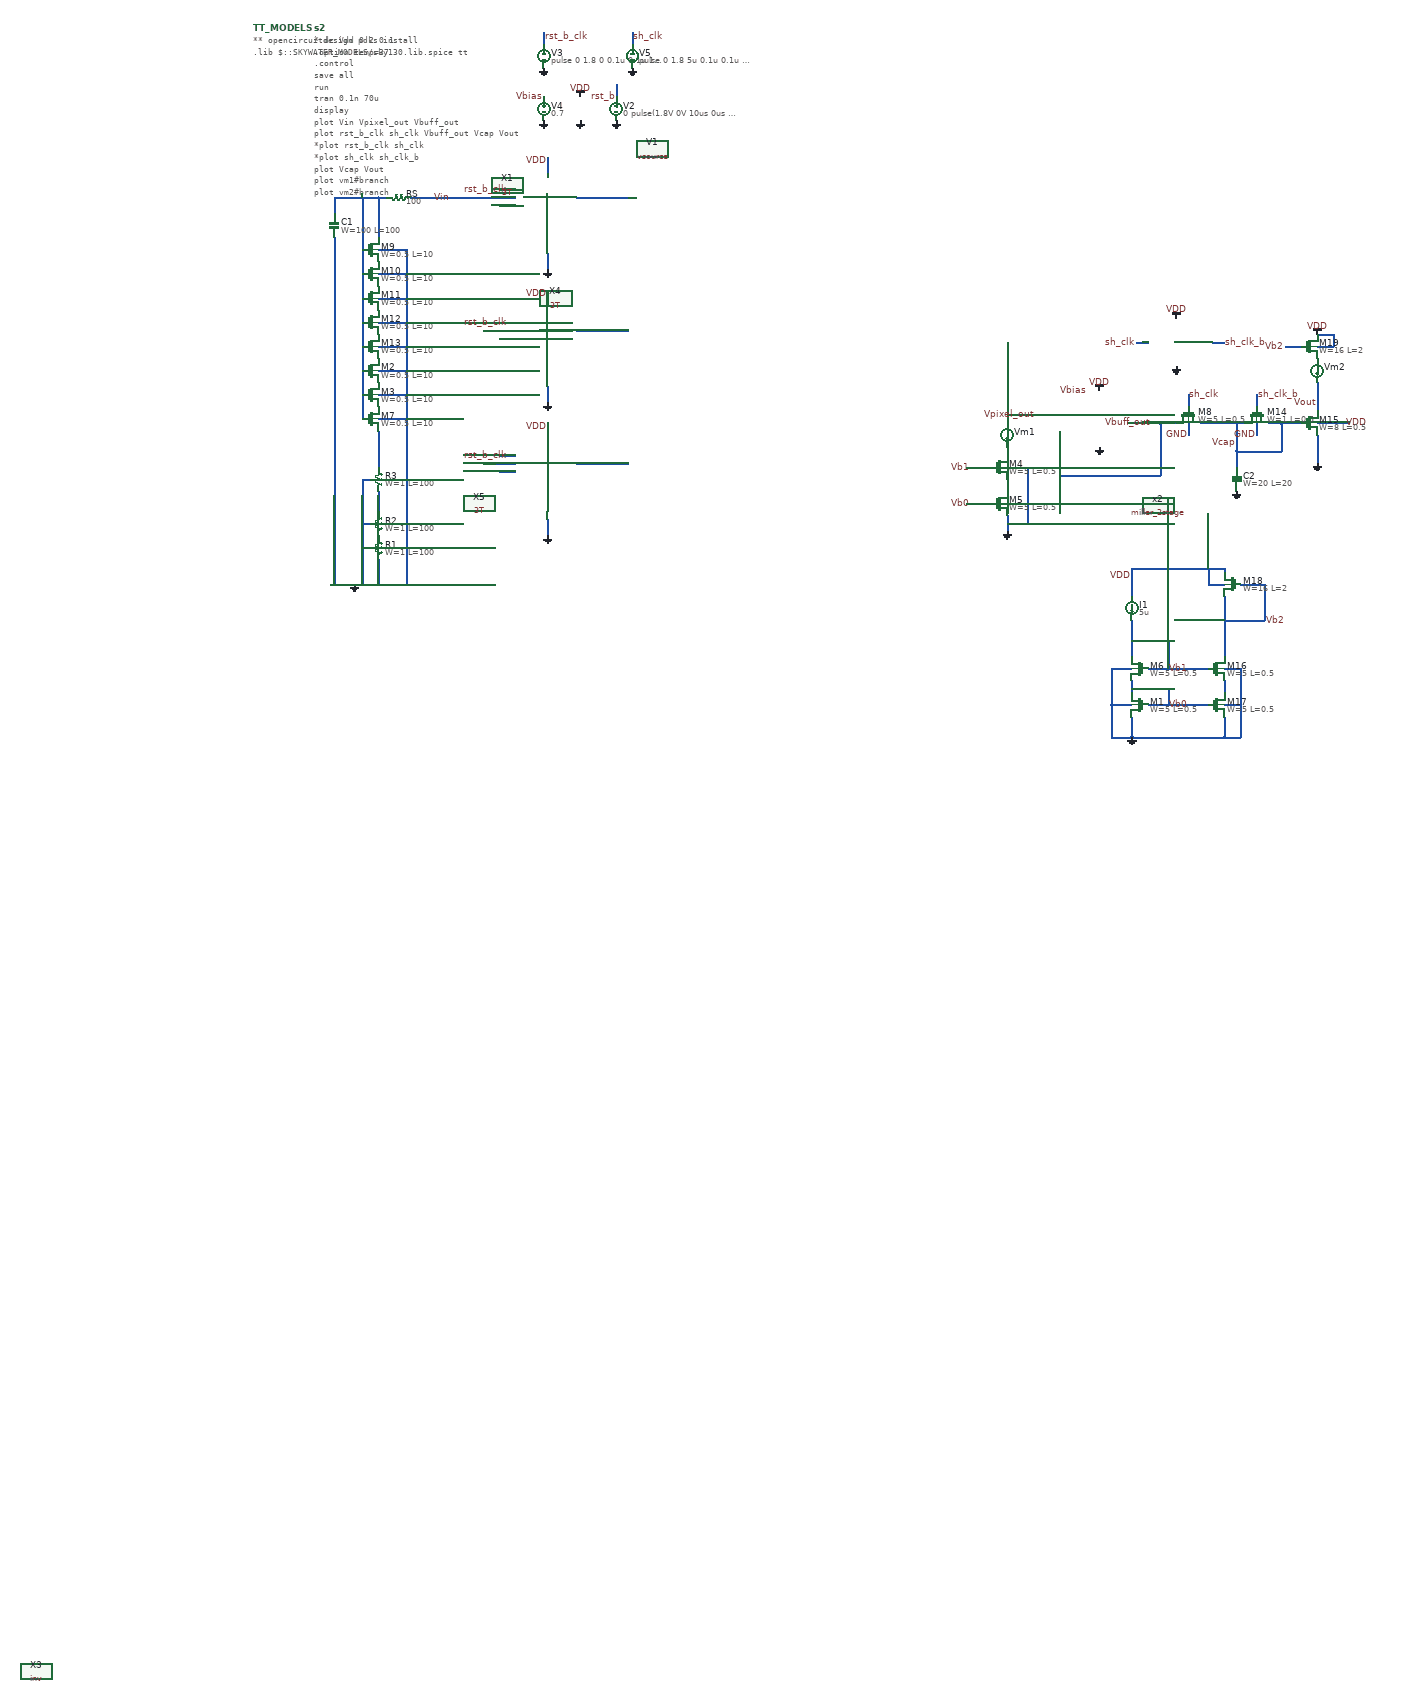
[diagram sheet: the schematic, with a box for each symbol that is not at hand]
v {xschem version=3.1.0 file_version=1.2
}
G {}
K {}
V {}
S {}
E {}
N 3910 -2230 3910 -2170 {
lab=Vpixel_out}
N 3910 -2030 3910 -2000 {
lab=#net1}
N 3910 -1940 3910 -1900 {
lab=GND}
N 3810 -1970 3870 -1970 {
lab=Vb0}
N 3810 -2060 3870 -2060 {
lab=Vb1}
N 2240 -2730 2240 -2690 {
lab=#net2}
N 2230 -1770 2340 -1770 {
lab=GND}
N 2350 -2730 2370 -2730 {
lab=#net2}
N 2430 -2730 2460 -2730 {
lab=Vin}
N 4220 -1530 4220 -1500 {
lab=Vb0}
N 4220 -1680 4220 -1590 {
lab=Vb1}
N 4220 -1440 4220 -1390 {
lab=GND}
N 4170 -1470 4220 -1470 {
lab=GND}
N 4170 -1470 4170 -1390 {
lab=GND}
N 4170 -1390 4220 -1390 {
lab=GND}
N 4170 -1560 4170 -1470 {
lab=GND}
N 4170 -1560 4220 -1560 {
lab=GND}
N 4260 -1470 4360 -1470 {
lab=Vb0}
N 4260 -1560 4360 -1560 {
lab=Vb1}
N 4220 -1630 4310 -1630 {
lab=Vb1}
N 4310 -1630 4310 -1560 {
lab=Vb1}
N 4220 -1510 4310 -1510 {
lab=Vb0}
N 4310 -1510 4310 -1470 {
lab=Vb0}
N 4220 -1810 4220 -1740 {
lab=VDD}
N 3910 -2190 4010 -2190 {
lab=Vpixel_out}
N 3910 -2110 3910 -2090 {
lab=#net3}
N 3910 -1970 3960 -1970 {
lab=GND}
N 3960 -1970 3960 -1920 {
lab=GND}
N 3910 -1920 3960 -1920 {
lab=GND}
N 3960 -2060 3960 -1970 {
lab=GND}
N 3910 -2060 3960 -2060 {
lab=GND}
N 4010 -2190 4040 -2190 {
lab=Vpixel_out}
N 2310 -2730 2310 -2660 {
lab=#net2}
N 2240 -2630 2240 -2210 {
lab=GND}
N 2240 -2210 2240 -1770 {
lab=GND}
N 2420 -2000 2420 -1770 {
lab=GND}
N 2840 -2730 2970 -2730 {
lab=#net4}
N 3910 -2370 3910 -2230 {
lab=Vpixel_out}
N 2770 -2830 2770 -2790 {
lab=VDD}
N 2770 -2590 2770 -2550 {
lab=GND}
N 2610 -2730 2690 -2730 {
lab=Vin}
N 2650 -2750 2690 -2750 {
lab=rst_b_clk}
N 2650 -2710 2690 -2710 {
lab=VDD}
N 2460 -2730 2610 -2730 {
lab=Vin}
N 2310 -1800 2310 -1770 {
lab=GND}
N 2310 -1920 2330 -1920 {
lab=GND}
N 2310 -1920 2310 -1800 {
lab=GND}
N 2350 -1970 2350 -1950 {
lab=#net5}
N 2310 -2420 2310 -2360 {
lab=#net2}
N 2310 -2480 2310 -2420 {
lab=#net2}
N 2310 -2540 2310 -2480 {
lab=#net2}
N 2310 -2600 2310 -2540 {
lab=#net2}
N 2310 -2660 2310 -2600 {
lab=#net2}
N 2350 -2600 2420 -2600 {
lab=GND}
N 2420 -2600 2420 -2210 {
lab=GND}
N 2350 -2420 2420 -2420 {
lab=GND}
N 2350 -2480 2420 -2480 {
lab=GND}
N 2350 -2540 2420 -2540 {
lab=GND}
N 2350 -2730 2350 -2630 {
lab=#net2}
N 2420 -2210 2420 -2000 {
lab=GND}
N 2350 -2360 2420 -2360 {
lab=GND}
N 2310 -2240 2310 -2180 {
lab=#net2}
N 2310 -2300 2310 -2240 {
lab=#net2}
N 2350 -2240 2420 -2240 {
lab=GND}
N 2350 -2300 2420 -2300 {
lab=GND}
N 2350 -2180 2420 -2180 {
lab=GND}
N 2310 -2360 2310 -2300 {
lab=#net2}
N 2760 -3130 2760 -3110 {
lab=rst_b_clk}
N 2760 -3140 2760 -3130 {
lab=rst_b_clk}
N 2940 -3010 2940 -2980 {
lab=rst_b}
N 2350 -2000 2350 -1970 {
lab=#net5}
N 2350 -2150 2350 -2060 {
lab=#net6}
N 2310 -2030 2330 -2030 {
lab=GND}
N 2310 -2030 2310 -1920 {
lab=GND}
N 2350 -1830 2350 -1770 {
lab=GND}
N 2310 -1860 2330 -1860 {
lab=GND}
N 4040 -2150 4040 -2040 {
lab=Vbuff_out}
N 4040 -2040 4290 -2040 {
lab=Vbuff_out}
N 4290 -2170 4290 -2040 {
lab=Vbuff_out}
N 4210 -2170 4290 -2170 {
lab=Vbuff_out}
N 4480 -2170 4480 -2100 {
lab=Vcap}
N 4480 -2100 4590 -2100 {
lab=Vcap}
N 4590 -2170 4590 -2100 {
lab=Vcap}
N 4680 -2270 4680 -2200 {
lab=Vout}
N 4680 -2140 4680 -2070 {
lab=GND}
N 4290 -2170 4330 -2170 {
lab=Vbuff_out}
N 4360 -2170 4360 -2140 {
lab=GND}
N 4530 -2170 4530 -2140 {
lab=GND}
N 4480 -2100 4480 -2060 {
lab=Vcap}
N 4680 -2170 4760 -2170 {
lab=VDD}
N 2980 -3130 2980 -3110 {
lab=sh_clk}
N 2980 -3140 2980 -3130 {
lab=sh_clk}
N 4360 -2240 4360 -2210 {
lab=sh_clk}
N 4230 -2370 4260 -2370 {
lab=sh_clk}
N 4420 -2370 4450 -2370 {
lab=sh_clk_b}
N 4530 -2240 4530 -2210 {
lab=sh_clk_b}
N 4390 -2170 4480 -2170 {
lab=Vcap}
N 4590 -2170 4640 -2170 {
lab=Vcap}
N 4480 -2170 4500 -2170 {
lab=Vcap}
N 4560 -2170 4590 -2170 {
lab=Vcap}
N 4360 -1560 4410 -1560 {
lab=Vb1}
N 4360 -1470 4410 -1470 {
lab=Vb0}
N 4450 -1440 4450 -1390 {
lab=GND}
N 4220 -1390 4450 -1390 {
lab=GND}
N 4450 -1470 4490 -1470 {
lab=GND}
N 4490 -1470 4490 -1390 {
lab=GND}
N 4450 -1390 4490 -1390 {
lab=GND}
N 4490 -1560 4490 -1470 {
lab=GND}
N 4450 -1560 4490 -1560 {
lab=GND}
N 4450 -1740 4450 -1590 {
lab=Vb2}
N 4220 -1810 4450 -1810 {
lab=VDD}
N 4450 -1810 4450 -1800 {
lab=VDD}
N 4450 -1680 4550 -1680 {
lab=Vb2}
N 4550 -1770 4550 -1680 {
lab=Vb2}
N 4490 -1770 4550 -1770 {
lab=Vb2}
N 4600 -2360 4640 -2360 {
lab=Vb2}
N 4680 -2360 4720 -2360 {
lab=VDD}
N 4720 -2390 4720 -2360 {
lab=VDD}
N 4680 -2390 4720 -2390 {
lab=VDD}
N 4450 -1530 4450 -1500 {
lab=#net7}
N 4410 -1770 4450 -1770 {
lab=VDD}
N 4410 -1810 4410 -1770 {
lab=VDD}
N 2340 -1770 2420 -1770 {
lab=GND}
N 2240 -2730 2350 -2730 {
lab=#net2}
N 2840 -2400 2970 -2400 {
lab=#net4}
N 2770 -2500 2770 -2460 {
lab=VDD}
N 2770 -2260 2770 -2220 {
lab=GND}
N 2610 -2400 2690 -2400 {
lab=Vin}
N 2650 -2420 2690 -2420 {
lab=rst_b_clk}
N 2650 -2380 2690 -2380 {
lab=VDD}
N 2840 -2070 2970 -2070 {
lab=#net4}
N 2770 -2170 2770 -2130 {
lab=VDD}
N 2770 -1930 2770 -1890 {
lab=GND}
N 2610 -2070 2690 -2070 {
lab=Vin}
N 2650 -2090 2690 -2090 {
lab=rst_b_clk}
N 2650 -2050 2690 -2050 {
lab=VDD}
C {sky130_fd_pr/nfet_01v8_lvt.sym} 3890 -2060 0 0 {name=M4
L=0.5
W=5
nf=2
mult=1
ad="'int((nf+1)/2) * W/nf * 0.29'" 
pd="'2*int((nf+1)/2) * (W/nf + 0.29)'"
as="'int((nf+2)/2) * W/nf * 0.29'" 
ps="'2*int((nf+2)/2) * (W/nf + 0.29)'"
nrd="'0.29 / W'" nrs="'0.29 / W'"
sa=0 sb=0 sd=0
model=nfet_01v8_lvt
spiceprefix=X
}
C {sky130_fd_pr/nfet_01v8_lvt.sym} 3890 -1970 0 0 {name=M5
L=0.5
W=5
nf=2
mult=1
ad="'int((nf+1)/2) * W/nf * 0.29'" 
pd="'2*int((nf+1)/2) * (W/nf + 0.29)'"
as="'int((nf+2)/2) * W/nf * 0.29'" 
ps="'2*int((nf+2)/2) * (W/nf + 0.29)'"
nrd="'0.29 / W'" nrs="'0.29 / W'"
sa=0 sb=0 sd=0
model=nfet_01v8_lvt
spiceprefix=X
}
C {gnd.sym} 2290 -1770 0 0 {name=l1 lab=GND}
C {gnd.sym} 3910 -1900 0 0 {name=l1 lab=GND}
C {res.sym} 2400 -2730 1 0 {name=RS
value=100
footprint=1206
device=resistor
m=1}
C {sky130_fd_pr/nfet_01v8_lvt.sym} 4240 -1560 0 1 {name=M6
L=0.5
W=5
nf=2
mult=1
ad="'int((nf+1)/2) * W/nf * 0.29'" 
pd="'2*int((nf+1)/2) * (W/nf + 0.29)'"
as="'int((nf+2)/2) * W/nf * 0.29'" 
ps="'2*int((nf+2)/2) * (W/nf + 0.29)'"
nrd="'0.29 / W'" nrs="'0.29 / W'"
sa=0 sb=0 sd=0
model=nfet_01v8_lvt
spiceprefix=X
}
C {sky130_fd_pr/nfet_01v8_lvt.sym} 4240 -1470 0 1 {name=M1
L=0.5
W=5
nf=2
mult=1
ad="'int((nf+1)/2) * W/nf * 0.29'" 
pd="'2*int((nf+1)/2) * (W/nf + 0.29)'"
as="'int((nf+2)/2) * W/nf * 0.29'" 
ps="'2*int((nf+2)/2) * (W/nf + 0.29)'"
nrd="'0.29 / W'" nrs="'0.29 / W'"
sa=0 sb=0 sd=0
model=nfet_01v8_lvt
spiceprefix=X
}
C {gnd.sym} 4220 -1390 0 0 {name=l1 lab=GND}
C {isource.sym} 4220 -1710 0 0 {name=I1 value=5u}
C {lab_wire.sym} 4220 -1790 0 0 {name=l1 sig_type=std_logic lab=VDD}
C {lab_wire.sym} 4360 -1560 0 0 {name=l1 sig_type=std_logic lab=Vb1}
C {lab_wire.sym} 4360 -1470 0 0 {name=l1 sig_type=std_logic lab=Vb0}
C {lab_wire.sym} 3820 -2060 0 0 {name=l1 sig_type=std_logic lab=Vb1}
C {lab_wire.sym} 3820 -1970 0 0 {name=l2 sig_type=std_logic lab=Vb0}
C {devices/vsource.sym} 2850 -2950 0 0 {name=V1 net_name=true 
*value="'VDD' pwl 0us 0 1us 'VDD'"
value=1.8}
C {devices/vdd.sym} 2850 -2980 0 0 {name=l9 lab=VDD}
C {devices/gnd.sym} 2850 -2920 0 0 {name=l22 lab=GND}
C {devices/code.sym} 2040 -3150 0 0 {name=TT_MODELS
only_toplevel=true
format="tcleval( @value )"
value="
** opencircuitdesign pdks install
.lib $::SKYWATER_MODELS/sky130.lib.spice tt

"
spice_ignore=false}
C {devices/code_shown.sym} 2190 -3150 0 0 {name=s2 only_toplevel=false value="
*.dc Vdd 0 2 0.1
.option temp=37
.control
save all
run
tran 0.1n 70u
display

plot Vin Vpixel_out Vbuff_out
plot rst_b_clk sh_clk Vbuff_out Vcap Vout
*plot rst_b_clk sh_clk
*plot sh_clk sh_clk_b
plot Vcap Vout
plot vm1#branch
plot vm2#branch
*plot vm3#branch

.endc
"}
C {devices/ammeter.sym} 3910 -2140 0 0 {name=Vm1 current=40e-6}
C {devices/vsource.sym} 2940 -2950 0 0 {name=V2 net_name=true value="0 pulse(1.8V 0V 10us 0us 0us 5us)"}
C {devices/gnd.sym} 2940 -2920 0 0 {name=l12 lab=GND}
C {devices/lab_pin.sym} 2940 -2980 0 0 {name=l23 lab=rst_b}
C {cmos_imager/3T.sym} 2650 -2710 0 0 {name=X1}
C {lab_wire.sym} 2770 -2820 0 0 {name=l1 sig_type=std_logic lab=VDD}
C {gnd.sym} 2770 -2550 0 0 {name=l1 lab=GND}
C {devices/lab_pin.sym} 2670 -2750 0 0 {name=l23 lab=rst_b_clk}
C {lab_wire.sym} 2530 -2730 0 0 {name=l1 sig_type=std_logic lab=Vin}
C {sky130_fd_pr/cap_mim_m3_1.sym} 2240 -2660 0 0 {name=C1 model=cap_mim_m3_1 W=100 L=100 MF=1 spiceprefix=X}
C {sky130_fd_pr/res_xhigh_po_5p73.sym} 2350 -1860 0 0 {name=R1
W=1
L=100
model=res_xhigh_po_5p73
spiceprefix=X
mult=1}
C {sky130_fd_pr/res_xhigh_po_5p73.sym} 2350 -1920 0 0 {name=R2
W=1
L=100
model=res_xhigh_po_5p73
spiceprefix=X
mult=1}
C {sky130_fd_pr/nfet_01v8_lvt.sym} 2330 -2600 0 0 {name=M9
L=10
W=0.5
nf=1
mult=1
ad="'int((nf+1)/2) * W/nf * 0.29'" 
pd="'2*int((nf+1)/2) * (W/nf + 0.29)'"
as="'int((nf+2)/2) * W/nf * 0.29'" 
ps="'2*int((nf+2)/2) * (W/nf + 0.29)'"
nrd="'0.29 / W'" nrs="'0.29 / W'"
sa=0 sb=0 sd=0
model=nfet_01v8_lvt
spiceprefix=X
}
C {sky130_fd_pr/nfet_01v8_lvt.sym} 2330 -2540 0 0 {name=M10
L=10
W=0.5
nf=1
mult=1
ad="'int((nf+1)/2) * W/nf * 0.29'" 
pd="'2*int((nf+1)/2) * (W/nf + 0.29)'"
as="'int((nf+2)/2) * W/nf * 0.29'" 
ps="'2*int((nf+2)/2) * (W/nf + 0.29)'"
nrd="'0.29 / W'" nrs="'0.29 / W'"
sa=0 sb=0 sd=0
model=nfet_01v8_lvt
spiceprefix=X
}
C {sky130_fd_pr/nfet_01v8_lvt.sym} 2330 -2480 0 0 {name=M11
L=10
W=0.5
nf=1
mult=1
ad="'int((nf+1)/2) * W/nf * 0.29'" 
pd="'2*int((nf+1)/2) * (W/nf + 0.29)'"
as="'int((nf+2)/2) * W/nf * 0.29'" 
ps="'2*int((nf+2)/2) * (W/nf + 0.29)'"
nrd="'0.29 / W'" nrs="'0.29 / W'"
sa=0 sb=0 sd=0
model=nfet_01v8_lvt
spiceprefix=X
}
C {sky130_fd_pr/nfet_01v8_lvt.sym} 2330 -2420 0 0 {name=M12
L=10
W=0.5
nf=1
mult=1
ad="'int((nf+1)/2) * W/nf * 0.29'" 
pd="'2*int((nf+1)/2) * (W/nf + 0.29)'"
as="'int((nf+2)/2) * W/nf * 0.29'" 
ps="'2*int((nf+2)/2) * (W/nf + 0.29)'"
nrd="'0.29 / W'" nrs="'0.29 / W'"
sa=0 sb=0 sd=0
model=nfet_01v8_lvt
spiceprefix=X
}
C {sky130_fd_pr/nfet_01v8_lvt.sym} 2330 -2360 0 0 {name=M13
L=10
W=0.5
nf=1
mult=1
ad="'int((nf+1)/2) * W/nf * 0.29'" 
pd="'2*int((nf+1)/2) * (W/nf + 0.29)'"
as="'int((nf+2)/2) * W/nf * 0.29'" 
ps="'2*int((nf+2)/2) * (W/nf + 0.29)'"
nrd="'0.29 / W'" nrs="'0.29 / W'"
sa=0 sb=0 sd=0
model=nfet_01v8_lvt
spiceprefix=X
}
C {sky130_fd_pr/nfet_01v8_lvt.sym} 2330 -2300 0 0 {name=M2
L=10
W=0.5
nf=1
mult=1
ad="'int((nf+1)/2) * W/nf * 0.29'" 
pd="'2*int((nf+1)/2) * (W/nf + 0.29)'"
as="'int((nf+2)/2) * W/nf * 0.29'" 
ps="'2*int((nf+2)/2) * (W/nf + 0.29)'"
nrd="'0.29 / W'" nrs="'0.29 / W'"
sa=0 sb=0 sd=0
model=nfet_01v8_lvt
spiceprefix=X
}
C {sky130_fd_pr/nfet_01v8_lvt.sym} 2330 -2240 0 0 {name=M3
L=10
W=0.5
nf=1
mult=1
ad="'int((nf+1)/2) * W/nf * 0.29'" 
pd="'2*int((nf+1)/2) * (W/nf + 0.29)'"
as="'int((nf+2)/2) * W/nf * 0.29'" 
ps="'2*int((nf+2)/2) * (W/nf + 0.29)'"
nrd="'0.29 / W'" nrs="'0.29 / W'"
sa=0 sb=0 sd=0
model=nfet_01v8_lvt
spiceprefix=X
}
C {sky130_fd_pr/nfet_01v8_lvt.sym} 2330 -2180 0 0 {name=M7
L=10
W=0.5
nf=1
mult=1
ad="'int((nf+1)/2) * W/nf * 0.29'" 
pd="'2*int((nf+1)/2) * (W/nf + 0.29)'"
as="'int((nf+2)/2) * W/nf * 0.29'" 
ps="'2*int((nf+2)/2) * (W/nf + 0.29)'"
nrd="'0.29 / W'" nrs="'0.29 / W'"
sa=0 sb=0 sd=0
model=nfet_01v8_lvt
spiceprefix=X
}
C {devices/vsource.sym} 2760 -3080 0 0 {name=V3 value="pulse 0 1.8 0 0.1u 0.1u 15u 20u"}
C {devices/gnd.sym} 2760 -3050 0 0 {name=l12 lab=GND}
C {devices/lab_pin.sym} 2760 -3130 0 1 {name=l23 lab=rst_b_clk}
C {noconn.sym} 2760 -3140 0 0 {name=l2}
C {noconn.sym} 2940 -3010 0 0 {name=l1}
C {sky130_fd_pr/res_xhigh_po_5p73.sym} 2350 -2030 0 0 {name=R3
W=1
L=100
model=res_xhigh_po_5p73
spiceprefix=X
mult=1}
C {ip_block/opamp/miller_2stage/miller_2stage.sym} 4140 -2170 0 0 {name=x2}
C {gnd.sym} 4140 -2110 0 0 {name=l3 lab=GND}
C {devices/vdd.sym} 4140 -2250 0 0 {name=l9 lab=VDD}
C {devices/vsource.sym} 2760 -2950 0 0 {name=V4 value=0.7}
C {lab_wire.sym} 2760 -2980 0 0 {name=l5 sig_type=std_logic lab=Vbias
}
C {devices/gnd.sym} 2760 -2920 0 1 {name=l3 lab=GND}
C {lab_wire.sym} 4110 -2250 0 0 {name=l5 sig_type=std_logic lab=Vbias
}
C {lab_wire.sym} 4270 -2170 0 0 {name=l3 sig_type=std_logic lab=Vbuff_out}
C {lab_wire.sym} 3980 -2190 0 0 {name=l3 sig_type=std_logic lab=Vpixel_out}
C {sky130_fd_pr/nfet_01v8_lvt.sym} 4360 -2190 3 1 {name=M8
L=0.5
W=5
nf=1
mult=1
ad="'int((nf+1)/2) * W/nf * 0.29'" 
pd="'2*int((nf+1)/2) * (W/nf + 0.29)'"
as="'int((nf+2)/2) * W/nf * 0.29'" 
ps="'2*int((nf+2)/2) * (W/nf + 0.29)'"
nrd="'0.29 / W'" nrs="'0.29 / W'"
sa=0 sb=0 sd=0
model=nfet_01v8_lvt
spiceprefix=X
}
C {sky130_fd_pr/nfet_01v8_lvt.sym} 4530 -2190 3 1 {name=M14
L=0.5
W=1
nf=1
mult=1
ad="'int((nf+1)/2) * W/nf * 0.29'" 
pd="'2*int((nf+1)/2) * (W/nf + 0.29)'"
as="'int((nf+2)/2) * W/nf * 0.29'" 
ps="'2*int((nf+2)/2) * (W/nf + 0.29)'"
nrd="'0.29 / W'" nrs="'0.29 / W'"
sa=0 sb=0 sd=0
model=nfet_01v8_lvt
spiceprefix=X
}
C {lab_wire.sym} 4680 -2220 0 0 {name=l3 sig_type=std_logic lab=Vout}
C {devices/vdd.sym} 4680 -2390 0 0 {name=l9 lab=VDD}
C {lab_wire.sym} 4360 -2140 3 0 {name=l3 sig_type=std_logic lab=GND}
C {lab_wire.sym} 4530 -2140 3 0 {name=l3 sig_type=std_logic lab=GND}
C {gnd.sym} 4680 -2070 0 0 {name=l3 lab=GND}
C {sky130_fd_pr/cap_mim_m3_1.sym} 4480 -2030 0 0 {name=C2 model=cap_mim_m3_1 W=20 L=20 MF=1 spiceprefix=X}
C {gnd.sym} 4480 -2000 0 0 {name=l3 lab=GND}
C {lab_wire.sym} 4750 -2170 0 1 {name=l3 sig_type=std_logic lab=VDD}
C {devices/vsource.sym} 2980 -3080 0 0 {name=V5 value="pulse 0 1.8 5u 0.1u 0.1u 5u 20u"}
C {devices/gnd.sym} 2980 -3050 0 0 {name=l12 lab=GND}
C {devices/lab_pin.sym} 2980 -3130 0 1 {name=l23 lab=sh_clk}
C {noconn.sym} 2980 -3140 0 0 {name=l3}
C {devices/lab_pin.sym} 4360 -2240 0 1 {name=l23 lab=sh_clk}
C {ip_block/logic_gate/inv.sym} 1500 930 0 0 {name=X3}
C {devices/lab_pin.sym} 4230 -2370 0 0 {name=l23 lab=sh_clk}
C {devices/lab_pin.sym} 4450 -2370 0 1 {name=l23 lab=sh_clk_b}
C {devices/lab_pin.sym} 4530 -2240 0 1 {name=l23 lab=sh_clk_b}
C {devices/vdd.sym} 4330 -2430 0 0 {name=l9 lab=VDD}
C {devices/gnd.sym} 4330 -2310 0 0 {name=l12 lab=GND}
C {lab_wire.sym} 4480 -2120 0 0 {name=l4 sig_type=std_logic lab=Vcap}
C {sky130_fd_pr/pfet_01v8_lvt.sym} 4660 -2170 0 0 {name=M15
L=0.5
W=8
nf=1
mult=20
ad="'int((nf+1)/2) * W/nf * 0.29'" 
pd="'2*int((nf+1)/2) * (W/nf + 0.29)'"
as="'int((nf+2)/2) * W/nf * 0.29'" 
ps="'2*int((nf+2)/2) * (W/nf + 0.29)'"
nrd="'0.29 / W'" nrs="'0.29 / W'"
sa=0 sb=0 sd=0
model=pfet_01v8_lvt
spiceprefix=X
}
C {sky130_fd_pr/nfet_01v8_lvt.sym} 4430 -1560 0 0 {name=M16
L=0.5
W=5
nf=2
mult=1
ad="'int((nf+1)/2) * W/nf * 0.29'" 
pd="'2*int((nf+1)/2) * (W/nf + 0.29)'"
as="'int((nf+2)/2) * W/nf * 0.29'" 
ps="'2*int((nf+2)/2) * (W/nf + 0.29)'"
nrd="'0.29 / W'" nrs="'0.29 / W'"
sa=0 sb=0 sd=0
model=nfet_01v8_lvt
spiceprefix=X
}
C {sky130_fd_pr/nfet_01v8_lvt.sym} 4430 -1470 0 0 {name=M17
L=0.5
W=5
nf=2
mult=1
ad="'int((nf+1)/2) * W/nf * 0.29'" 
pd="'2*int((nf+1)/2) * (W/nf + 0.29)'"
as="'int((nf+2)/2) * W/nf * 0.29'" 
ps="'2*int((nf+2)/2) * (W/nf + 0.29)'"
nrd="'0.29 / W'" nrs="'0.29 / W'"
sa=0 sb=0 sd=0
model=nfet_01v8_lvt
spiceprefix=X
}
C {sky130_fd_pr/pfet_01v8_lvt.sym} 4470 -1770 0 1 {name=M18
L=2
W=16
nf=1
mult=8
ad="'int((nf+1)/2) * W/nf * 0.29'" 
pd="'2*int((nf+1)/2) * (W/nf + 0.29)'"
as="'int((nf+2)/2) * W/nf * 0.29'" 
ps="'2*int((nf+2)/2) * (W/nf + 0.29)'"
nrd="'0.29 / W'" nrs="'0.29 / W'"
sa=0 sb=0 sd=0
model=pfet_01v8_lvt
spiceprefix=X
}
C {lab_wire.sym} 4550 -1680 0 1 {name=l4 sig_type=std_logic lab=Vb2}
C {sky130_fd_pr/pfet_01v8_lvt.sym} 4660 -2360 0 0 {name=M19
L=2
W=16
nf=1
mult=8
ad="'int((nf+1)/2) * W/nf * 0.29'" 
pd="'2*int((nf+1)/2) * (W/nf + 0.29)'"
as="'int((nf+2)/2) * W/nf * 0.29'" 
ps="'2*int((nf+2)/2) * (W/nf + 0.29)'"
nrd="'0.29 / W'" nrs="'0.29 / W'"
sa=0 sb=0 sd=0
model=pfet_01v8_lvt
spiceprefix=X
}
C {lab_wire.sym} 4600 -2360 0 0 {name=l4 sig_type=std_logic lab=Vb2}
C {devices/ammeter.sym} 4680 -2300 0 0 {name=Vm2 current=40e-6}
C {cmos_imager/3T.sym} 2650 -2380 0 0 {name=X4}
C {lab_wire.sym} 2770 -2490 0 0 {name=l4 sig_type=std_logic lab=VDD}
C {gnd.sym} 2770 -2220 0 0 {name=l5 lab=GND}
C {devices/lab_pin.sym} 2670 -2420 0 0 {name=l23 lab=rst_b_clk}
C {cmos_imager/3T.sym} 2650 -2050 0 0 {name=X5}
C {lab_wire.sym} 2770 -2160 0 0 {name=l4 sig_type=std_logic lab=VDD}
C {gnd.sym} 2770 -1890 0 0 {name=l5 lab=GND}
C {devices/lab_pin.sym} 2670 -2090 0 0 {name=l23 lab=rst_b_clk}
